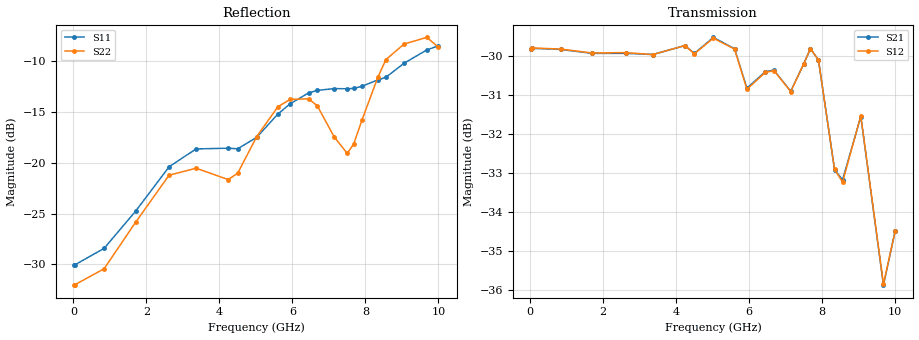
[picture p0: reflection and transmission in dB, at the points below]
! Integrated Device Technology
! Corporate Headquarters
! 6024 Silver Creek Valley Road
! San Jose, CA 95138  USA
! Phone:  1-408-284-8200
! Toll Free:  1-800-223-1366
! Webpage:  http://www.idt.com/
! Timing and RF Division
! 515 Groton Road, Suite 102
! Westford, MA 01886-6024
! Device:  F1958
! Description: 7-bit 0.25 dB Digital Step Attenuator
! Frequency:  0.001 -  6.000 GHz
! Package:  4x4 mm Thin QFN Plastic Package: 24 pin
! Ports:  2 RF, 12 DC
!  Pin  1  = D0
!  Pin  2  = VDD
!  Pin  3  = VMODE
!  Pin  4  = GND
!  Pin  5  = RF1  =  Port 1
!  Pin  6  = GND
!  Pin  7  = GND
!  Pin  8  = GND
!  Pin  9  = GND
!  Pin 10  = GND
!  Pin 11  = GND
!  Pin 12  = GND
!  Pin 13  = GND
!  Pin 14  = RF2  =  Port 2
!  Pin 15  = GND
!  Pin 16  = LE
!  Pin 17  = CLK
!  Pin 18  = DATA
!  Pin 19  = D6
!  Pin 20  = D5
!  Pin 21  = D4
!  Pin 22  = D3
!  Pin 23  = D2
!  Pin 24  = D1
! State:  116
! Atten State:  29.00 dB
! Voltage:  +3.30 Volts
! Current:  0.258 mA
! Data:  The device was measured on a F1958 evaluation board which has
!  individual transmission lines to the RF pins.  Data was collected
!  using a calibrated network analyzer.  The evaluation board was
!  de-embedded using Automatic Fixture Removal (AFR).
!  The reference plane is the edge of the package pin.
! Misc:
!  Action Tracker AT0419
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# GHz S dB R 50
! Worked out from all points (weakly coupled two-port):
!   500 points, 20 MHz to 10 GHz, reference 50 ohm
!   highest |S21| = -29.53 dB at 5.02 GHz (marker M1); lowest = -35.9 dB at 9.68 GHz (marker M2)
!   lowest |S11| = -30.0 dB at 40 MHz (marker M3), VSWR 1.06, Z = 47 - j0.0441 ohm
!   |S11| at or under -10 dB: start of sweep to 9.15 GHz
!   |S22| runs from -32.3 to -7.5 dB; largest |S21 - S12| = 0.00024
!   S11 on the Smith chart (normalised r, x): 20 MHz: 0.94, -0.00; 6.44 GHz: 0.67, +0.17; 10 GHz: 0.68, +0.58
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0.02  -30.02 -178.9  -29.82 -0.2  -29.82 -0.2  -32.05 -178.9
0.04  -30.05 -179.1  -29.81 -0.4  -29.80 -0.3  -32.01 -178.4
0.84  -28.43 170.7  -29.84 -9.6  -29.83 -9.6  -30.44 172.0
1.7  -24.78 170.6  -29.94 -19.2  -29.93 -19.3  -25.87 170.9
2.62  -20.40 176.7  -29.94 -29.6  -29.92 -29.6  -21.23 -179.7
3.36  -18.64 -175.9  -29.97 -38.4  -29.97 -38.7  -20.54 -169.4
4.24  -18.57 -179.2  -29.74 -48.6  -29.74 -48.6  -21.66 168.9
4.5  -18.63 174.9  -29.94 -52.3  -29.95 -52.4  -21.03 151.3
5.02  -17.50 160.6  -29.53 -58.9  -29.55 -58.9  -17.43 138.2
5.6  -15.21 150.6  -29.82 -67.7  -29.83 -67.7  -14.49 140.2
5.94  -14.19 148.2  -30.83 -72.0  -30.86 -72.0  -13.76 148.7
6.44  -13.13 147.8  -30.41 -77.6  -30.43 -77.6  -13.71 157.9
6.68  -12.88 146.7  -30.37 -80.3  -30.38 -80.2  -14.39 158.0
7.14  -12.70 142.8  -30.91 -86.2  -30.92 -86.1  -17.44 152.3
7.5  -12.72 138.4  -30.20 -89.9  -30.20 -89.7  -19.08 120.4
7.68  -12.68 135.5  -29.82 -95.3  -29.82 -95.3  -18.14 100.0
7.9  -12.48 129.0  -30.11 -104.7  -30.11 -104.8  -15.84 89.6
8.34  -11.85 118.9  -32.92 -111.9  -32.91 -111.9  -11.58 84.2
8.56  -11.59 115.3  -33.18 -104.0  -33.24 -104.1  -9.85 86.6
9.06  -10.20 106.8  -31.56 -114.8  -31.54 -114.8  -8.31 97.9
9.68  -8.90 100.4  -35.88 -110.8  -35.85 -110.5  -7.66 111.0
10  -8.49 100.0  -34.50 -98.2  -34.50 -98.0  -8.63 114.3
